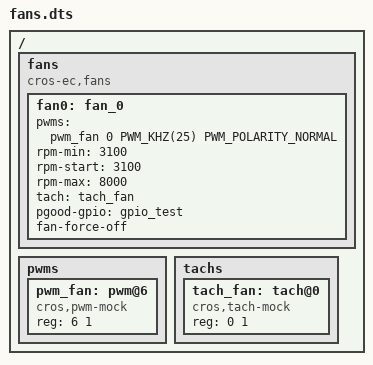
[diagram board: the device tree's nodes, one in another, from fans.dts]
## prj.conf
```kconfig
# Copyright 2023 The ChromiumOS Authors
# Use of this source code is governed by a BSD-style license that can be
# found in the LICENSE file.

CONFIG_PLATFORM_EC_TEMP_SENSOR_FIRST_READ_DELAY=y
CONFIG_PLATFORM_EC_TEMP_SENSOR_FIRST_READ_DELAY_MS=0
```

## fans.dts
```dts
/* Copyright 2023 The ChromiumOS Authors
 * Use of this source code is governed by a BSD-style license that can be
 * found in the LICENSE file.
 */

/ {
	fans {
		compatible = "cros-ec,fans";

		fan0: fan_0 {
			pwms = <&pwm_fan 0 PWM_KHZ(25) PWM_POLARITY_NORMAL>;
			rpm-min = <3100>;
			rpm-start = <3100>;
			rpm-max = <8000>;
			tach = <&tach_fan>;
			pgood-gpio = <&gpio_test>;
			fan-force-off;
		};
	};
	pwms {
		pwm_fan: pwm@6 {
			compatible = "cros,pwm-mock";
			reg = <6 1>;
			#pwm-cells = <3>;
			status = "okay";
		};
	};
	tachs {
		#address-cells = <1>;
		#size-cells = <1>;

		tach_fan: tach@0 {
			compatible = "cros,tach-mock";
			reg = <0 1>;
			#tach-cells = <3>;
			status = "okay";
		};
	};
};
```

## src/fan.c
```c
/* Copyright 2023 The ChromiumOS Authors
 * Use of this source code is governed by a BSD-style license that can be
 * found in the LICENSE file.
 */

#include "ec_commands.h"
#include "fan.h"
#include "gpio.h"
#include "include/power.h"
#include "thermal.h"
#include "test/drivers/test_state.h"
#include "test/drivers/utils.h"

#include <zephyr/ztest.h>

#define GPIO_PG_PATH NAMED_GPIOS_GPIO_NODE(test)
#define GPIO_PG_PORT DT_GPIO_PIN(GPIO_PG_PATH, gpios)

void pwm_fan_init(void);

struct fan_common_fixture {
	const struct device *pwm_mock;
	const struct device *tach_mock;
	const struct device *pgood_pin;
};

static void *fan_common_setup(void)
{
	static struct fan_common_fixture fixture;

	fixture.pwm_mock = DEVICE_DT_GET(DT_NODELABEL(pwm_fan));
	fixture.tach_mock = DEVICE_DT_GET(DT_NODELABEL(tach_fan));
	fixture.pgood_pin = DEVICE_DT_GET(DT_GPIO_CTLR(GPIO_PG_PATH, gpios));

	return &fixture;
}

static void fan_common_before(void *data)
{
	struct fan_common_fixture *fixture = (struct fan_common_fixture *)data;

	/* Always start in S0, the state fans usually are on in */
	test_set_chipset_to_s0();

	/* Restore how many fans we have */
	fan_set_count(CONFIG_FANS);

	/* Ensure PGOOD pin is set */
	zassert_ok(gpio_emul_input_set(fixture->pgood_pin, GPIO_PG_PORT, 1));
}

ZTEST_SUITE(fan_common, drivers_predicate_post_main, fan_common_setup,
	    fan_common_before, NULL, NULL);

ZTEST(fan_common, test_faninfo)
{
	CHECK_CONSOLE_CMD("faninfo", "Duty:", EC_SUCCESS);
}

ZTEST(fan_common, test_fanauto)
{
	CHECK_CONSOLE_CMD("fanauto", NULL, EC_SUCCESS);
}

ZTEST(fan_common, test_fanset_no_fans)
{
	/* Pretend we have no fans */
	fan_set_count(0);

	CHECK_CONSOLE_CMD("fanset", "zero", EC_ERROR_INVAL);
}

ZTEST(fan_common, test_fanset_no_arg)
{
	CHECK_CONSOLE_CMD("fanset", NULL, EC_ERROR_PARAM_COUNT);
}

ZTEST(fan_common, test_fanset_too_many_args)
{
	CHECK_CONSOLE_CMD("fanset 1 2 3 4 5", NULL, EC_ERROR_PARAM_COUNT);
}

ZTEST(fan_common, test_fanset_bad_fan)
{
	CHECK_CONSOLE_CMD("fanset 80 0", NULL, EC_ERROR_PARAM1);
}

ZTEST(fan_common, test_fanset_valid_2_arg)
{
	CHECK_CONSOLE_CMD("fanset 0 80", "Setting fan", EC_SUCCESS);
}

ZTEST(fan_common, test_fanset_valid_1_arg)
{
	CHECK_CONSOLE_CMD("fanset 80%", "Setting fan", EC_SUCCESS);
}

ZTEST(fan_common, test_fanduty_no_fans)
{
	/* Pretend we have no fans */
	fan_set_count(0);

	CHECK_CONSOLE_CMD("fanduty", "zero", EC_ERROR_INVAL);
}

ZTEST(fan_common, test_fanduty_no_arg)
{
	CHECK_CONSOLE_CMD("fanduty", NULL, EC_ERROR_PARAM_COUNT);
}

ZTEST(fan_common, test_fanduty_too_many_args)
{
	CHECK_CONSOLE_CMD("fanduty 1 2 3 4 5", NULL, EC_ERROR_PARAM_COUNT);
}

ZTEST(fan_common, test_fanduty_bad_fan)
{
	CHECK_CONSOLE_CMD("fanduty 80 0", NULL, EC_ERROR_PARAM1);
}

ZTEST(fan_common, test_fanduty_valid_2_arg)
{
	CHECK_CONSOLE_CMD("fanduty 0 80", "Setting fan", EC_SUCCESS);
}

ZTEST(fan_common, test_fanduty_valid_1_arg)
{
	CHECK_CONSOLE_CMD("fanduty 80", "Setting fan", EC_SUCCESS);
}

static const int temp_fan_off = C_TO_K(20);
static const int temp_fan_max = C_TO_K(40);
static const struct fan_step_1_1 test_table[] = {
	{ .decreasing_temp_ratio_threshold = TEMP_TO_RATIO(20),
	  .increasing_temp_ratio_threshold = TEMP_TO_RATIO(34),
	  .rpm = 1000 },
	{ .decreasing_temp_ratio_threshold = TEMP_TO_RATIO(39),
	  .increasing_temp_ratio_threshold = TEMP_TO_RATIO(40),
	  .rpm = 2000 },
};

static bool change;

static void test_on_change(void)
{
	change = true;
}

ZTEST(fan_common, test_fan_hysteresis)
{
	/* Start the fan off */
	change = false;
	fan_set_rpm_target(0, 0);

	/* Start the temperature below off threshold */
	zassert_equal(temp_ratio_to_rpm_hysteresis(test_table, 2, 0,
						   TEMP_TO_RATIO(10),
						   &test_on_change),
		      0);
	zassert_false(change);

	/* Increase, but stay below level 0 increase threshold */
	zassert_equal(temp_ratio_to_rpm_hysteresis(test_table, 2, 0,
						   TEMP_TO_RATIO(30),
						   &test_on_change),
		      0);
	zassert_false(change);

	/* Increase to level 0 */
	zassert_equal(temp_ratio_to_rpm_hysteresis(test_table, 2, 0,
						   TEMP_TO_RATIO(35),
						   &test_on_change),
		      1000);
	zassert_true(change);

	/* Increase to level 1 */
	change = false;
	zassert_equal(temp_ratio_to_rpm_hysteresis(test_table, 2, 0,
						   TEMP_TO_RATIO(45),
						   &test_on_change),
		      2000);
	zassert_true(change);

	/* Decrease back to level 0 */
	change = false;
	zassert_equal(temp_ratio_to_rpm_hysteresis(test_table, 2, 0,
						   TEMP_TO_RATIO(38),
						   &test_on_change),
		      1000);
	zassert_true(change);
}

ZTEST(fan_common, test_fan_hc_get_target_rpm)
{
	struct ec_response_pwm_get_fan_rpm r;
	struct host_cmd_handler_args args = BUILD_HOST_COMMAND_RESPONSE(
		EC_CMD_PWM_GET_FAN_TARGET_RPM, 0, r);

	zassert_ok(host_command_process(&args));
	zassert_equal(args.response_size, sizeof(r));
	zassert_equal(r.rpm, fan_get_rpm_target(0));
}

ZTEST(fan_common, test_fan_hc_get_target_rpm_no_fans)
{
	struct ec_response_pwm_get_fan_rpm r;
	struct host_cmd_handler_args args = BUILD_HOST_COMMAND_RESPONSE(
		EC_CMD_PWM_GET_FAN_TARGET_RPM, 0, r);

	/* Pretend we have no fans */
	fan_set_count(0);

	zassert_equal(host_command_process(&args), EC_RES_ERROR);
}

ZTEST(fan_common, test_fan_hc_set_target_rpm_v0)
{
	struct ec_params_pwm_set_fan_target_rpm_v0 p = {
		.rpm = 4000,
	};
	struct host_cmd_handler_args args =
		BUILD_HOST_COMMAND_PARAMS(EC_CMD_PWM_SET_FAN_TARGET_RPM, 0, p);

	zassert_ok(host_command_process(&args));
	zassert_equal(p.rpm, fan_get_rpm_target(0));
}

ZTEST(fan_common, test_fan_hc_set_target_rpm_v1)
{
	struct ec_params_pwm_set_fan_target_rpm_v1 p = {
		.rpm = 4000,
		.fan_idx = 0,
	};
	struct host_cmd_handler_args args =
		BUILD_HOST_COMMAND_PARAMS(EC_CMD_PWM_SET_FAN_TARGET_RPM, 1, p);

	zassert_ok(host_command_process(&args));
	zassert_equal(p.rpm, fan_get_rpm_target(0));
}

ZTEST(fan_common, test_fan_hc_set_target_rpm_v1_bad_fan)
{
	struct ec_params_pwm_set_fan_target_rpm_v1 p = {
		.rpm = 4000,
		.fan_idx = 80,
	};
	struct host_cmd_handler_args args =
		BUILD_HOST_COMMAND_PARAMS(EC_CMD_PWM_SET_FAN_TARGET_RPM, 1, p);

	zassert_equal(host_command_process(&args), EC_RES_ERROR);
}

ZTEST(fan_common, test_fan_hc_set_duty_v0)
{
	struct ec_params_pwm_set_fan_duty_v0 p = {
		.percent = 50,
	};
	struct host_cmd_handler_args args =
		BUILD_HOST_COMMAND_PARAMS(EC_CMD_PWM_SET_FAN_DUTY, 0, p);

	zassert_ok(host_command_process(&args));
}

ZTEST(fan_common, test_fan_hc_set_duty_v1)
{
	struct ec_params_pwm_set_fan_duty_v1 p = {
		.percent = 50,
		.fan_idx = 0,
	};
	struct host_cmd_handler_args args =
		BUILD_HOST_COMMAND_PARAMS(EC_CMD_PWM_SET_FAN_DUTY, 1, p);

	zassert_ok(host_command_process(&args));
}

ZTEST(fan_common, test_fan_hc_set_duty_v1_bad_fan)
{
	struct ec_params_pwm_set_fan_duty_v1 p = {
		.percent = 50,
		.fan_idx = 20,
	};
	struct host_cmd_handler_args args =
		BUILD_HOST_COMMAND_PARAMS(EC_CMD_PWM_SET_FAN_DUTY, 1, p);

	zassert_equal(host_command_process(&args), EC_RES_ERROR);
}

ZTEST(fan_common, test_fan_hc_get_duty)
{
	struct ec_params_pwm_get_fan_duty req = { .fan_idx = 0 };
	struct ec_response_pwm_get_fan_duty resp;
	struct host_cmd_handler_args args =
		BUILD_HOST_COMMAND(EC_CMD_PWM_GET_FAN_DUTY, 0, resp, req);

	zassert_ok(host_command_process(&args));
	zassert_equal(args.response_size, sizeof(resp));
	zassert_equal(resp.percent, fan_get_duty(0));
}

ZTEST(fan_common, test_fan_hc_get_duty_bad)
{
	struct ec_params_pwm_get_fan_duty req = { .fan_idx = 80 };
	struct ec_response_pwm_get_fan_duty resp;
	struct host_cmd_handler_args args =
		BUILD_HOST_COMMAND(EC_CMD_PWM_GET_FAN_DUTY, 0, resp, req);

	zassert_equal(host_command_process(&args), EC_RES_INVALID_PARAM);
}

void set_thermal_control_enabled(int fan, int enable);

ZTEST(fan_common, test_fan_hc_set_auto_fan_v0)
{
	struct host_cmd_handler_args args =
		BUILD_HOST_COMMAND_SIMPLE(EC_CMD_THERMAL_AUTO_FAN_CTRL, 0);

	set_thermal_control_enabled(0, 0);
	zassert_ok(host_command_process(&args));
	zassert_true(is_thermal_control_enabled(0));
}

ZTEST(fan_common, test_fan_hc_set_auto_fan_v1)
{
	struct ec_params_auto_fan_ctrl_v1 p = {
		.fan_idx = 0,
	};
	struct host_cmd_handler_args args =
		BUILD_HOST_COMMAND_PARAMS(EC_CMD_THERMAL_AUTO_FAN_CTRL, 1, p);

	set_thermal_control_enabled(0, 0);
	zassert_ok(host_command_process(&args));
	zassert_true(is_thermal_control_enabled(0));
}

ZTEST(fan_common, test_fan_hc_set_auto_fan_v1_bad_fan)
{
	struct ec_params_auto_fan_ctrl_v1 p = {
		.fan_idx = 20,
	};
	struct host_cmd_handler_args args =
		BUILD_HOST_COMMAND_PARAMS(EC_CMD_THERMAL_AUTO_FAN_CTRL, 1, p);

	zassert_equal(host_command_process(&args), EC_RES_INVALID_PARAM);
}

ZTEST(fan_common, test_fan_hc_set_auto_fan_v2)
{
	struct ec_params_auto_fan_ctrl_v2 req = {
		.fan_idx = 0,
		.cmd = EC_AUTO_FAN_CONTROL_CMD_SET,
		.set_auto = true,
	};
	struct host_cmd_handler_args args =
		BUILD_HOST_COMMAND_PARAMS(EC_CMD_THERMAL_AUTO_FAN_CTRL, 2, req);

	set_thermal_control_enabled(0, 0);
	zassert_ok(host_command_process(&args));
	zassert_true(is_thermal_control_enabled(0));

	req.set_auto = false;
	zassert_ok(host_command_process(&args));
	zassert_false(is_thermal_control_enabled(0));
}

ZTEST(fan_common, test_fan_hc_set_auto_fan_v2_bad)
{
	struct ec_params_auto_fan_ctrl_v2 req = {
		.fan_idx = 80,
		.cmd = EC_AUTO_FAN_CONTROL_CMD_SET,
		.set_auto = true,
	};
	struct host_cmd_handler_args args =
		BUILD_HOST_COMMAND_PARAMS(EC_CMD_THERMAL_AUTO_FAN_CTRL, 2, req);

	zassert_equal(host_command_process(&args), EC_RES_INVALID_PARAM);
}

ZTEST(fan_common, test_fan_hc_set_auto_fan_v2_get)
{
	struct ec_params_auto_fan_ctrl_v2 req = {
		.fan_idx = 0,
		.cmd = EC_AUTO_FAN_CONTROL_CMD_GET,
	};
	struct ec_response_auto_fan_control resp;
	struct host_cmd_handler_args args =
		BUILD_HOST_COMMAND(EC_CMD_THERMAL_AUTO_FAN_CTRL, 2, resp, req);

	set_thermal_control_enabled(0, 0);
	zassert_ok(host_command_process(&args));
	zassert_equal(args.response_size, sizeof(resp));
	zassert_false(resp.is_auto);

	set_thermal_control_enabled(0, 1);
	zassert_ok(host_command_process(&args));
	zassert_equal(args.response_size, sizeof(resp));
	zassert_true(resp.is_auto);
}

ZTEST(fan_common, test_fan_hc_set_auto_fan_v2_get_bad)
{
	struct ec_params_auto_fan_ctrl_v2 req = {
		.fan_idx = 80,
		.cmd = EC_AUTO_FAN_CONTROL_CMD_GET,
	};
	struct host_cmd_handler_args args =
		BUILD_HOST_COMMAND_PARAMS(EC_CMD_THERMAL_AUTO_FAN_CTRL, 2, req);

	zassert_equal(host_command_process(&args), EC_RES_INVALID_PARAM);
}

ZTEST(fan_common, test_fan_hc_set_auto_fan_v2_bad_cmd)
{
	struct ec_params_auto_fan_ctrl_v2 req = {
		.fan_idx = 0,
		.cmd = 255,
	};
	struct host_cmd_handler_args args =
		BUILD_HOST_COMMAND_PARAMS(EC_CMD_THERMAL_AUTO_FAN_CTRL, 2, req);

	zassert_equal(host_command_process(&args), EC_RES_INVALID_PARAM);
}

ZTEST(fan_common, test_memmap_not_present)
{
	uint16_t *mapped = (uint16_t *)host_get_memmap(EC_MEMMAP_FAN);

	/* Initial reported speeds are zero. */
	for (int i = 0; i < EC_FAN_SPEED_ENTRIES; i++) {
		mapped[i] = 0;
	}

	/* Reported speeds are set to NOT_PRESENT as appropriate. */
	fan_set_count(0);
	pwm_fan_init();
	for (int i = 0; i < EC_FAN_SPEED_ENTRIES; i++) {
		zassert_equal(
			mapped[i], EC_FAN_SPEED_NOT_PRESENT,
			"Fan %d reports speed %d but should not be present", i,
			mapped[i]);
	}
}

ZTEST(fan_common, test_fan_set_percent_needed)
{
	int initial_target;
	const struct gpio_dt_spec *gp = GPIO_DT_FROM_NODELABEL(gpio_test);

	/* Ensure thermal control is enabled for fan 0 */
	set_thermal_control_enabled(0, 1);

	/* Test: Setting 0% should set RPM target to 0 */
	fan_set_percent_needed(0, 0);
	zassert_equal(fan_get_rpm_target(0), 0,
		      "Fan target should be 0 RPM at 0%%");
	/* Verify GPIO is turned off when RPM target is 0 */
	zassert_equal(gpio_emul_output_get(gp->port, gp->pin), 0,
		      "GPIO should be off when RPM is 0");

	/* Test: Setting 100% should set RPM to max */
	fan_set_percent_needed(0, 100);
	zassert_equal(fan_get_rpm_target(0), fans[0].rpm->rpm_max,
		      "Fan target should be max RPM at 100%%");
	/* Verify GPIO is turned on when RPM target is non-zero */
	zassert_equal(gpio_emul_output_get(gp->port, gp->pin), 1,
		      "GPIO should be on when RPM is non-zero");

	/* Test: Setting a mid-range percentage (e.g., 50%) */
	fan_set_percent_needed(0, 50);
	initial_target = fan_get_rpm_target(0);
	zassert_true(initial_target > 0 &&
			     initial_target <= fans[0].rpm->rpm_max,
		     "Fan target at 50%% should be between 0 and max RPM");
	/* Verify GPIO remains on for mid-range RPM */
	zassert_equal(gpio_emul_output_get(gp->port, gp->pin), 1,
		      "GPIO should be on when RPM is non-zero");
}

static struct fan_step_1_1 temp_fan_table[] = {
	{ .increasing_temp_ratio_threshold = 41,
	  .decreasing_temp_ratio_threshold = 35,
	  .rpm = 2500 },
	{ .increasing_temp_ratio_threshold = 43,
	  .decreasing_temp_ratio_threshold = 41,
	  .rpm = 3200 },
	{ .increasing_temp_ratio_threshold = 45,
	  .decreasing_temp_ratio_threshold = 43,
	  .rpm = 3500 },
	{ .increasing_temp_ratio_threshold = 47,
	  .decreasing_temp_ratio_threshold = 45,
	  .rpm = 3900 },
	{ .increasing_temp_ratio_threshold = 49,
	  .decreasing_temp_ratio_threshold = 47,
	  .rpm = 4500 },
	{ .increasing_temp_ratio_threshold = 52,
	  .decreasing_temp_ratio_threshold = 48,
	  .rpm = 5100 },
	{ .increasing_temp_ratio_threshold = 55,
	  .decreasing_temp_ratio_threshold = 50,
	  .rpm = 5400 },
};

static int temp_to_rpm(int temp)
{
	int rpm = temp_ratio_to_rpm_hysteresis(temp_fan_table,
					     ARRAY_SIZE(temp_fan_table), 0,
					     temp, NULL);
	fan_set_rpm_target(0, rpm);
	return rpm;
}

ZTEST(fan_common, test_temp_ratio_to_rpm_hysteresis)
{
	fan_set_rpm_target(0, 0);

	zassert_equal(temp_to_rpm(30), 0);
	zassert_equal(temp_to_rpm(35), 0);
	zassert_equal(temp_to_rpm(40), 0);
	zassert_equal(temp_to_rpm(41), 2500);
	zassert_equal(temp_to_rpm(36), 2500);
	zassert_equal(temp_to_rpm(42), 2500);
	zassert_equal(temp_to_rpm(43), 3200);
	zassert_equal(temp_to_rpm(38), 3200);
	zassert_equal(temp_to_rpm(45), 3500);
	zassert_equal(temp_to_rpm(47), 3900);
	zassert_equal(temp_to_rpm(49), 4500);
	zassert_equal(temp_to_rpm(52), 5100);
	zassert_equal(temp_to_rpm(55), 5400);
	zassert_equal(temp_to_rpm(60), 5400);

	/* Cool-down hysteresis */
	zassert_equal(temp_to_rpm(55), 5400);
	zassert_equal(temp_to_rpm(52), 5400);
	zassert_equal(temp_to_rpm(51), 5100);
	zassert_equal(temp_to_rpm(48), 4500);
	zassert_equal(temp_to_rpm(46), 3900);
	zassert_equal(temp_to_rpm(44), 3500);
	zassert_equal(temp_to_rpm(42), 3200);
	zassert_equal(temp_to_rpm(37), 2500);
	zassert_equal(temp_to_rpm(35), 0);
}
```

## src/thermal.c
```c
/* Copyright 2026 The ChromiumOS Authors
 * Use of this source code is governed by a BSD-style license that can be
 * found in the LICENSE file.
 */

#include "ap_reset_log.h"
#include "chipset.h"
#include "common.h"
#include "ec_commands.h"
#include "fan.h"
#include "hooks.h"
#include "host_command.h"
#include "temp_sensor.h"
#include "temp_sensor/temp_sensor.h"
#include "test/drivers/test_state.h"
#include "test/drivers/utils.h"
#include "thermal.h"

#include <zephyr/drivers/adc.h>
#include <zephyr/drivers/adc/adc_emul.h>
#include <zephyr/drivers/gpio.h>
#include <zephyr/drivers/gpio/gpio_emul.h>
#include <zephyr/ztest.h>

#define GPIO_PG_EC_DSW_PWROK_PATH NAMED_GPIOS_GPIO_NODE(pg_ec_dsw_pwrok)
#define GPIO_PG_EC_DSW_PWROK_PORT DT_GPIO_PIN(GPIO_PG_EC_DSW_PWROK_PATH, gpios)

#define GPIO_EC_PG_PIN_TEMP_PATH NAMED_GPIOS_GPIO_NODE(ec_pg_pin_temp)
#define GPIO_EC_PG_PIN_TEMP_PORT DT_GPIO_PIN(GPIO_EC_PG_PIN_TEMP_PATH, gpios)

#define GPIO_PG_FAN_PATH NAMED_GPIOS_GPIO_NODE(test)
#define GPIO_PG_FAN_PORT DT_GPIO_PIN(GPIO_PG_FAN_PATH, gpios)

#define ADC_CHANNELS_NUM DT_PROP(DT_NODELABEL(adc0), nchannels)

#define THERMAL_PARAMS_SIZE \
	(sizeof(struct ec_thermal_config) * TEMP_SENSOR_COUNT)

struct thermal_fixture {
	const struct device *pg_dsw_dev;
	const struct device *pg_temp_dev;
	const struct device *pg_fan_dev;
	struct ec_thermal_config initial_thermal_params[TEMP_SENSOR_COUNT];
#ifdef CONFIG_HOSTCMD_X86
	struct host_events_ctx host_events_ctx;
#endif
};
static struct thermal_fixture fixture;

extern test_export_static int first_read_delay;

static void seed_temp_sensors(void)
{
	const struct device *adc_dev = DEVICE_DT_GET(DT_NODELABEL(adc0));

	for (int chan = 0; chan < ADC_CHANNELS_NUM; chan++) {
		zassert_ok(adc_emul_const_value_set(adc_dev, chan, 1000),
			   "channel %d adc_emul_const_value_set() failed",
			   chan);
	}
}

static void *thermal_setup(void)
{
	fixture.pg_dsw_dev =
		DEVICE_DT_GET(DT_GPIO_CTLR(GPIO_PG_EC_DSW_PWROK_PATH, gpios));
	fixture.pg_temp_dev =
		DEVICE_DT_GET(DT_GPIO_CTLR(GPIO_EC_PG_PIN_TEMP_PATH, gpios));
	fixture.pg_fan_dev =
		DEVICE_DT_GET(DT_GPIO_CTLR(GPIO_PG_FAN_PATH, gpios));

	seed_temp_sensors();

	memcpy(fixture.initial_thermal_params, thermal_params,
	       THERMAL_PARAMS_SIZE);

#ifdef CONFIG_HOSTCMD_X86
	host_events_save(&fixture.host_events_ctx);
#endif

	return &fixture;
}

static void reset_thermal_state(struct thermal_fixture *fix)
{
	test_set_chipset_to_s0();
	fan_set_count(CONFIG_FANS);
	seed_temp_sensors();

	zassert_ok(gpio_emul_input_set(fix->pg_dsw_dev,
				       GPIO_PG_EC_DSW_PWROK_PORT, 1));
	zassert_ok(gpio_emul_input_set(fix->pg_temp_dev,
				       GPIO_EC_PG_PIN_TEMP_PORT, 1));
	zassert_ok(gpio_emul_input_set(fix->pg_fan_dev, GPIO_PG_FAN_PORT, 1));

	memcpy(thermal_params, fix->initial_thermal_params,
	       THERMAL_PARAMS_SIZE);

#ifdef CONFIG_HOSTCMD_X86
	host_events_restore(&fix->host_events_ctx);
#endif
}

static void thermal_before(void *data)
{
	struct thermal_fixture *fix = (struct thermal_fixture *)data;

	reset_thermal_state(fix);
}

static void thermal_after(void *data)
{
	struct thermal_fixture *fix = (struct thermal_fixture *)data;

	reset_thermal_state(fix);
	hook_notify(HOOK_SECOND);
}

ZTEST_SUITE(thermal, drivers_predicate_post_main, thermal_setup, thermal_before,
	    thermal_after, NULL);

ZTEST(thermal, test_thermal_fan_percent)
{
	/* cur < low */
	zassert_equal(thermal_fan_percent(100, 200, 50), 0);
	zassert_equal(thermal_fan_percent(100, 200, 99), 0);
	zassert_equal(thermal_fan_percent(100, 200, 100), 0);

	/* cur > high */
	zassert_equal(thermal_fan_percent(100, 200, 200), 100);
	zassert_equal(thermal_fan_percent(100, 200, 201), 100);
	zassert_equal(thermal_fan_percent(100, 200, 300), 100);

	/* intermediate values */
	zassert_equal(thermal_fan_percent(100, 200, 125), 25);
	zassert_equal(thermal_fan_percent(100, 200, 150), 50);
	zassert_equal(thermal_fan_percent(100, 200, 175), 75);
}

ZTEST(thermal, test_thermal_control_no_sensors_read)
{
#ifdef CONFIG_HOSTCMD_X86
	host_event_t lpc_event_mask;
	host_event_t mask = EC_HOST_EVENT_MASK(EC_HOST_EVENT_THERMAL);

	lpc_event_mask = lpc_get_host_event_mask(LPC_HOST_EVENT_SMI);
	lpc_set_host_event_mask(LPC_HOST_EVENT_SMI, lpc_event_mask | mask);
#endif

	/* Unpower sensors so none can be read */
	zassert_ok(gpio_emul_input_set(fixture.pg_temp_dev,
				       GPIO_EC_PG_PIN_TEMP_PORT, 0));

	/* In S0 (not hard off): triggers smi_sensor_failure_warning */
	host_clear_events(EC_HOST_EVENT_MASK(EC_HOST_EVENT_THERMAL));
	hook_notify(HOOK_SECOND);
	zassert_true(host_is_event_set(EC_HOST_EVENT_THERMAL));

	/* In G3 (hard off): does not trigger smi warning */
	test_set_chipset_to_g3();
	host_clear_events(EC_HOST_EVENT_MASK(EC_HOST_EVENT_THERMAL));
	hook_notify(HOOK_SECOND);
	zassert_false(host_is_event_set(EC_HOST_EVENT_THERMAL));

	/* Restore S0 */
	test_set_chipset_to_s0();
}

ZTEST(thermal, test_thermal_control_fan)
{
	int t = 0;

	zassert_ok(temp_sensor_read(0, &t));
	zassert_true(t > 0);

	/* Clear other sensors so sensor 0 dictates fan */
	memset(thermal_params, 0, THERMAL_PARAMS_SIZE);

	/* Case 1: Temp within range -> ~50% */
	thermal_params[0].temp_fan_off = t - 20;
	thermal_params[0].temp_fan_max = t + 20;
	hook_notify(HOOK_SECOND);
	/* Target RPM should be ~50% */
	zassert_equal(fan_get_rpm_target(0), fan_percent_to_rpm(0, 50));

	/* Case 2: Temp below fan_off -> 0% */
	thermal_params[0].temp_fan_off = t + 10;
	thermal_params[0].temp_fan_max = t + 20;
	hook_notify(HOOK_SECOND);
	zassert_equal(fan_get_rpm_target(0), 0);

	/* Case 3: Temp above fan_max -> 100% */
	thermal_params[0].temp_fan_off = t - 20;
	thermal_params[0].temp_fan_max = t - 10;
	hook_notify(HOOK_SECOND);
	zassert_equal(fan_get_rpm_target(0), fans[0].rpm->rpm_max);
}

ZTEST(thermal, test_thermal_control_thresholds)
{
	int t = 0;
	uint32_t resets;

	zassert_ok(temp_sensor_read(0, &t));
	zassert_true(t > 0);

	/* Clear other sensors so only sensor 0 is active */
	memset(thermal_params, 0, THERMAL_PARAMS_SIZE);

	/* Test WARN threshold */
	thermal_params[0].temp_host[EC_TEMP_THRESH_WARN] = t - 5;
	hook_notify(HOOK_SECOND);

	/* Cool down WARN */
	thermal_params[0].temp_host[EC_TEMP_THRESH_WARN] = t + 10;
	hook_notify(HOOK_SECOND);

	/* Test HIGH threshold */
	thermal_params[0].temp_host[EC_TEMP_THRESH_HIGH] = t - 5;
	hook_notify(HOOK_SECOND);

	/* Cool down HIGH */
	thermal_params[0].temp_host[EC_TEMP_THRESH_HIGH] = t + 10;
	hook_notify(HOOK_SECOND);

	/* Test HALT threshold */
	resets = test_chipset_get_ap_resets_since_ec_boot();
	thermal_params[0].temp_host[EC_TEMP_THRESH_HALT] = t - 5;
	hook_notify(HOOK_SECOND);
	zassert_equal(chipset_get_shutdown_reason(), CHIPSET_SHUTDOWN_THERMAL);
	zassert_equal(test_chipset_get_ap_resets_since_ec_boot(), resets + 1);

	/* Halting triggers chipset_force_shutdown. Restore S0. */
	test_set_chipset_to_s0();

	/* Cool down HALT */
	thermal_params[0].temp_host[EC_TEMP_THRESH_HALT] = t + 10;
	hook_notify(HOOK_SECOND);
}

ZTEST(thermal, test_thermal_control_release_hysteresis)
{
	int t = 0;
	uint32_t resets;

	zassert_ok(temp_sensor_read(0, &t));
	zassert_true(t > 0);

	memset(thermal_params, 0, THERMAL_PARAMS_SIZE);

	/* 1. Trip HALT: t > limit */
	resets = test_chipset_get_ap_resets_since_ec_boot();
	thermal_params[0].temp_host[EC_TEMP_THRESH_HALT] = t - 5;
	thermal_params[0].temp_host_release[EC_TEMP_THRESH_HALT] = t - 15;
	hook_notify(HOOK_SECOND);
	zassert_equal(chipset_get_shutdown_reason(), CHIPSET_SHUTDOWN_THERMAL);
	zassert_equal(test_chipset_get_ap_resets_since_ec_boot(), resets + 1);

	/* 2. In hysteresis band: release <= t <= limit. Should not
	 * clear/re-trip. */
	test_set_chipset_to_s0();
	resets = test_chipset_get_ap_resets_since_ec_boot();
	thermal_params[0].temp_host[EC_TEMP_THRESH_HALT] = t + 5;
	thermal_params[0].temp_host_release[EC_TEMP_THRESH_HALT] = t - 5;
	hook_notify(HOOK_SECOND);
	/* Re-heating above limit while still unreleased must not re-trigger */
	thermal_params[0].temp_host[EC_TEMP_THRESH_HALT] = t - 5;
	hook_notify(HOOK_SECOND);
	zassert_equal(test_chipset_get_ap_resets_since_ec_boot(), resets);

	/* 3. Cool down past release: t < release. Clears condition. */
	thermal_params[0].temp_host[EC_TEMP_THRESH_HALT] = t + 10;
	thermal_params[0].temp_host_release[EC_TEMP_THRESH_HALT] = t + 5;
	hook_notify(HOOK_SECOND);

	/* 4. Trip again: now that condition was cleared, it trips anew. */
	resets = test_chipset_get_ap_resets_since_ec_boot();
	thermal_params[0].temp_host[EC_TEMP_THRESH_HALT] = t - 5;
	thermal_params[0].temp_host_release[EC_TEMP_THRESH_HALT] = t - 15;
	hook_notify(HOOK_SECOND);
	zassert_equal(chipset_get_shutdown_reason(), CHIPSET_SHUTDOWN_THERMAL);
	zassert_equal(test_chipset_get_ap_resets_since_ec_boot(), resets + 1);

	/* Restore S0 and clear HALT */
	test_set_chipset_to_s0();
	thermal_params[0].temp_host[EC_TEMP_THRESH_HALT] = t + 10;
	thermal_params[0].temp_host_release[EC_TEMP_THRESH_HALT] = t + 5;
	hook_notify(HOOK_SECOND);
}

ZTEST(thermal, test_console_thermalget)
{
	CHECK_CONSOLE_CMD("thermalget", "sensor", EC_SUCCESS);
}

ZTEST(thermal, test_console_thermalset)
{
	/* Invalid param counts */
	CHECK_CONSOLE_CMD("thermalset", NULL, EC_ERROR_PARAM_COUNT);
	CHECK_CONSOLE_CMD("thermalset 0", NULL, EC_ERROR_PARAM_COUNT);
	CHECK_CONSOLE_CMD("thermalset 0 1 2 3 4 5 6 7", NULL,
			  EC_ERROR_PARAM_COUNT);

	/* Invalid parameters */
	CHECK_CONSOLE_CMD("thermalset abc 1 2", NULL, EC_ERROR_PARAM1);
	CHECK_CONSOLE_CMD("thermalset 0 bad", NULL, EC_ERROR_PARAM2);

	/* Valid set */
	CHECK_CONSOLE_CMD("thermalset 0 300 320 340 290 310", NULL, EC_SUCCESS);
	zassert_equal(thermal_params[0].temp_host[EC_TEMP_THRESH_WARN], 300);
	zassert_equal(thermal_params[0].temp_host[EC_TEMP_THRESH_HIGH], 320);
	zassert_equal(thermal_params[0].temp_host[EC_TEMP_THRESH_HALT], 340);
	zassert_equal(thermal_params[0].temp_fan_off, 290);
	zassert_equal(thermal_params[0].temp_fan_max, 310);

	/* Skip fields using -1 */
	CHECK_CONSOLE_CMD("thermalset 0 -1 -1 -1 -1 -1", NULL, EC_SUCCESS);
	zassert_equal(thermal_params[0].temp_host[EC_TEMP_THRESH_WARN], 300);
	zassert_equal(thermal_params[0].temp_host[EC_TEMP_THRESH_HIGH], 320);
	zassert_equal(thermal_params[0].temp_host[EC_TEMP_THRESH_HALT], 340);
	zassert_equal(thermal_params[0].temp_fan_off, 290);
	zassert_equal(thermal_params[0].temp_fan_max, 310);

	/* Partial update using -1 to skip specific fields */
	CHECK_CONSOLE_CMD("thermalset 0 -1 325 -1 -1 -1", NULL, EC_SUCCESS);
	zassert_equal(thermal_params[0].temp_host[EC_TEMP_THRESH_WARN], 300);
	zassert_equal(thermal_params[0].temp_host[EC_TEMP_THRESH_HIGH], 325);
	zassert_equal(thermal_params[0].temp_host[EC_TEMP_THRESH_HALT], 340);
	zassert_equal(thermal_params[0].temp_fan_off, 290);
	zassert_equal(thermal_params[0].temp_fan_max, 310);
}

ZTEST(thermal, test_hc_thermal_thresholds)
{
	struct ec_params_thermal_set_threshold_v1 set_p = {
		.sensor_num = 0,
		.cfg = {
			.temp_host = { 301, 321, 341 },
			.temp_host_release = { 291, 311, 331 },
			.temp_fan_off = 281,
			.temp_fan_max = 311,
		},
	};
	struct ec_params_thermal_get_threshold_v1 get_p = {
		.sensor_num = 0,
	};
	struct ec_thermal_config get_r = { 0 };

	/* Bad sensor num for SET */
	set_p.sensor_num = TEMP_SENSOR_COUNT;
	{
		struct host_cmd_handler_args args = BUILD_HOST_COMMAND_PARAMS(
			EC_CMD_THERMAL_SET_THRESHOLD, 1, set_p);
		zassert_equal(host_command_process(&args),
			      EC_RES_INVALID_PARAM);
	}

	/* Bad sensor num for GET */
	get_p.sensor_num = TEMP_SENSOR_COUNT;
	{
		struct host_cmd_handler_args args = BUILD_HOST_COMMAND(
			EC_CMD_THERMAL_GET_THRESHOLD, 1, get_r, get_p);
		zassert_equal(host_command_process(&args),
			      EC_RES_INVALID_PARAM);
	}

	/* Valid SET */
	set_p.sensor_num = 0;
	{
		struct host_cmd_handler_args args = BUILD_HOST_COMMAND_PARAMS(
			EC_CMD_THERMAL_SET_THRESHOLD, 1, set_p);
		zassert_ok(host_command_process(&args));
	}

	/* Valid GET */
	get_p.sensor_num = 0;
	{
		struct host_cmd_handler_args args = BUILD_HOST_COMMAND(
			EC_CMD_THERMAL_GET_THRESHOLD, 1, get_r, get_p);
		zassert_ok(host_command_process(&args));
		zassert_equal(args.response_size, sizeof(get_r));
		zassert_mem_equal(&get_r, &set_p.cfg, sizeof(get_r));
	}
}

ZTEST(thermal, test_thermal_control_first_read_delay)
{
	int t = 0;

	zassert_ok(temp_sensor_read(0, &t));
	zassert_true(t > 0);

	/* Set fan off / max so normal thermal_control would set 100% fan */
	memset(thermal_params, 0, THERMAL_PARAMS_SIZE);
	thermal_params[0].temp_fan_off = t - 20;
	thermal_params[0].temp_fan_max = t - 10;

	/* Reset fan target to 0 */
	fan_set_rpm_target(0, 0);
	zassert_equal(fan_get_rpm_target(0), 0);

	/* Set first_read_delay to 1500 ms (requiring 2 HOOK_SECOND ticks to
	 * clear) */
	first_read_delay = 1500;

	/* 1st HOOK_SECOND: first_read_delay decrements from 1500 to 500, no fan
	 * update */
	hook_notify(HOOK_SECOND);
	zassert_equal(first_read_delay, 500);
	zassert_equal(fan_get_rpm_target(0), 0);

	/* 2nd HOOK_SECOND: first_read_delay decrements from 500 to 0, no fan
	 * update */
	hook_notify(HOOK_SECOND);
	zassert_equal(first_read_delay, 0);
	zassert_equal(fan_get_rpm_target(0), 0);

	/* 3rd HOOK_SECOND: delay is 0, normal thermal_control runs and spins up
	 * fan */
	hook_notify(HOOK_SECOND);
	zassert_equal(first_read_delay, 0);
	zassert_equal(fan_get_rpm_target(0), fans[0].rpm->rpm_max);

	/* Cleanup */
	reset_thermal_state(&fixture);
}
```
